VERSION 5.7 ;
BUSBITCHARS "[]" ;
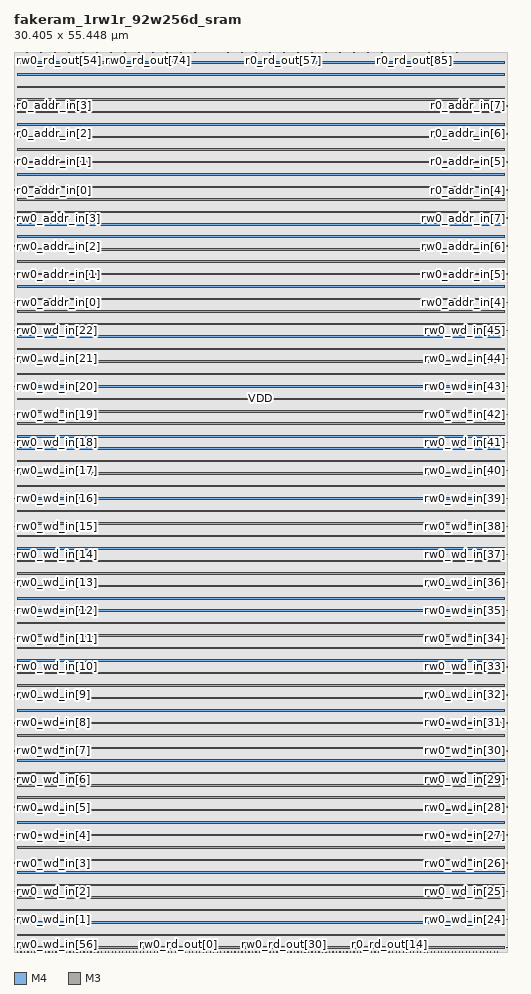
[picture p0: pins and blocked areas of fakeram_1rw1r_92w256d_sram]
MACRO fakeram_1rw1r_92w256d_sram
  FOREIGN fakeram_1rw1r_92w256d_sram 0 0 ;
  SYMMETRY X Y R90 ;
  SIZE 30.405 BY 55.448 ;
  CLASS BLOCK ;
  PIN rw0_wd_in[0]
    DIRECTION INPUT ;
    USE SIGNAL ;
    SHAPE ABUTMENT ;
    PORT
      LAYER M4 ;
      RECT 0.000 0.276 0.072 0.300 ;
    END
  END rw0_wd_in[0]
  PIN rw0_wd_in[1]
    DIRECTION INPUT ;
    USE SIGNAL ;
    SHAPE ABUTMENT ;
    PORT
      LAYER M4 ;
      RECT 0.000 2.004 0.072 2.028 ;
    END
  END rw0_wd_in[1]
  PIN rw0_wd_in[2]
    DIRECTION INPUT ;
    USE SIGNAL ;
    SHAPE ABUTMENT ;
    PORT
      LAYER M4 ;
      RECT 0.000 3.732 0.072 3.756 ;
    END
  END rw0_wd_in[2]
  PIN rw0_wd_in[3]
    DIRECTION INPUT ;
    USE SIGNAL ;
    SHAPE ABUTMENT ;
    PORT
      LAYER M4 ;
      RECT 0.000 5.460 0.072 5.484 ;
    END
  END rw0_wd_in[3]
  PIN rw0_wd_in[4]
    DIRECTION INPUT ;
    USE SIGNAL ;
    SHAPE ABUTMENT ;
    PORT
      LAYER M4 ;
      RECT 0.000 7.188 0.072 7.212 ;
    END
  END rw0_wd_in[4]
  PIN rw0_wd_in[5]
    DIRECTION INPUT ;
    USE SIGNAL ;
    SHAPE ABUTMENT ;
    PORT
      LAYER M4 ;
      RECT 0.000 8.916 0.072 8.940 ;
    END
  END rw0_wd_in[5]
  PIN rw0_wd_in[6]
    DIRECTION INPUT ;
    USE SIGNAL ;
    SHAPE ABUTMENT ;
    PORT
      LAYER M4 ;
      RECT 0.000 10.644 0.072 10.668 ;
    END
  END rw0_wd_in[6]
  PIN rw0_wd_in[7]
    DIRECTION INPUT ;
    USE SIGNAL ;
    SHAPE ABUTMENT ;
    PORT
      LAYER M4 ;
      RECT 0.000 12.372 0.072 12.396 ;
    END
  END rw0_wd_in[7]
  PIN rw0_wd_in[8]
    DIRECTION INPUT ;
    USE SIGNAL ;
    SHAPE ABUTMENT ;
    PORT
      LAYER M4 ;
      RECT 0.000 14.100 0.072 14.124 ;
    END
  END rw0_wd_in[8]
  PIN rw0_wd_in[9]
    DIRECTION INPUT ;
    USE SIGNAL ;
    SHAPE ABUTMENT ;
    PORT
      LAYER M4 ;
      RECT 0.000 15.828 0.072 15.852 ;
    END
  END rw0_wd_in[9]
  PIN rw0_wd_in[10]
    DIRECTION INPUT ;
    USE SIGNAL ;
    SHAPE ABUTMENT ;
    PORT
      LAYER M4 ;
      RECT 0.000 17.556 0.072 17.580 ;
    END
  END rw0_wd_in[10]
  PIN rw0_wd_in[11]
    DIRECTION INPUT ;
    USE SIGNAL ;
    SHAPE ABUTMENT ;
    PORT
      LAYER M4 ;
      RECT 0.000 19.284 0.072 19.308 ;
    END
  END rw0_wd_in[11]
  PIN rw0_wd_in[12]
    DIRECTION INPUT ;
    USE SIGNAL ;
    SHAPE ABUTMENT ;
    PORT
      LAYER M4 ;
      RECT 0.000 21.012 0.072 21.036 ;
    END
  END rw0_wd_in[12]
  PIN rw0_wd_in[13]
    DIRECTION INPUT ;
    USE SIGNAL ;
    SHAPE ABUTMENT ;
    PORT
      LAYER M4 ;
      RECT 0.000 22.740 0.072 22.764 ;
    END
  END rw0_wd_in[13]
  PIN rw0_wd_in[14]
    DIRECTION INPUT ;
    USE SIGNAL ;
    SHAPE ABUTMENT ;
    PORT
      LAYER M4 ;
      RECT 0.000 24.468 0.072 24.492 ;
    END
  END rw0_wd_in[14]
  PIN rw0_wd_in[15]
    DIRECTION INPUT ;
    USE SIGNAL ;
    SHAPE ABUTMENT ;
    PORT
      LAYER M4 ;
      RECT 0.000 26.196 0.072 26.220 ;
    END
  END rw0_wd_in[15]
  PIN rw0_wd_in[16]
    DIRECTION INPUT ;
    USE SIGNAL ;
    SHAPE ABUTMENT ;
    PORT
      LAYER M4 ;
      RECT 0.000 27.924 0.072 27.948 ;
    END
  END rw0_wd_in[16]
  PIN rw0_wd_in[17]
    DIRECTION INPUT ;
    USE SIGNAL ;
    SHAPE ABUTMENT ;
    PORT
      LAYER M4 ;
      RECT 0.000 29.652 0.072 29.676 ;
    END
  END rw0_wd_in[17]
  PIN rw0_wd_in[18]
    DIRECTION INPUT ;
    USE SIGNAL ;
    SHAPE ABUTMENT ;
    PORT
      LAYER M4 ;
      RECT 0.000 31.380 0.072 31.404 ;
    END
  END rw0_wd_in[18]
  PIN rw0_wd_in[19]
    DIRECTION INPUT ;
    USE SIGNAL ;
    SHAPE ABUTMENT ;
    PORT
      LAYER M4 ;
      RECT 0.000 33.108 0.072 33.132 ;
    END
  END rw0_wd_in[19]
  PIN rw0_wd_in[20]
    DIRECTION INPUT ;
    USE SIGNAL ;
    SHAPE ABUTMENT ;
    PORT
      LAYER M4 ;
      RECT 0.000 34.836 0.072 34.860 ;
    END
  END rw0_wd_in[20]
  PIN rw0_wd_in[21]
    DIRECTION INPUT ;
    USE SIGNAL ;
    SHAPE ABUTMENT ;
    PORT
      LAYER M4 ;
      RECT 0.000 36.564 0.072 36.588 ;
    END
  END rw0_wd_in[21]
  PIN rw0_wd_in[22]
    DIRECTION INPUT ;
    USE SIGNAL ;
    SHAPE ABUTMENT ;
    PORT
      LAYER M4 ;
      RECT 0.000 38.292 0.072 38.316 ;
    END
  END rw0_wd_in[22]
  PIN rw0_wd_in[23]
    DIRECTION INPUT ;
    USE SIGNAL ;
    SHAPE ABUTMENT ;
    PORT
      LAYER M4 ;
      RECT 30.333 0.276 30.405 0.300 ;
    END
  END rw0_wd_in[23]
  PIN rw0_wd_in[24]
    DIRECTION INPUT ;
    USE SIGNAL ;
    SHAPE ABUTMENT ;
    PORT
      LAYER M4 ;
      RECT 30.333 2.004 30.405 2.028 ;
    END
  END rw0_wd_in[24]
  PIN rw0_wd_in[25]
    DIRECTION INPUT ;
    USE SIGNAL ;
    SHAPE ABUTMENT ;
    PORT
      LAYER M4 ;
      RECT 30.333 3.732 30.405 3.756 ;
    END
  END rw0_wd_in[25]
  PIN rw0_wd_in[26]
    DIRECTION INPUT ;
    USE SIGNAL ;
    SHAPE ABUTMENT ;
    PORT
      LAYER M4 ;
      RECT 30.333 5.460 30.405 5.484 ;
    END
  END rw0_wd_in[26]
  PIN rw0_wd_in[27]
    DIRECTION INPUT ;
    USE SIGNAL ;
    SHAPE ABUTMENT ;
    PORT
      LAYER M4 ;
      RECT 30.333 7.188 30.405 7.212 ;
    END
  END rw0_wd_in[27]
  PIN rw0_wd_in[28]
    DIRECTION INPUT ;
    USE SIGNAL ;
    SHAPE ABUTMENT ;
    PORT
      LAYER M4 ;
      RECT 30.333 8.916 30.405 8.940 ;
    END
  END rw0_wd_in[28]
  PIN rw0_wd_in[29]
    DIRECTION INPUT ;
    USE SIGNAL ;
    SHAPE ABUTMENT ;
    PORT
      LAYER M4 ;
      RECT 30.333 10.644 30.405 10.668 ;
    END
  END rw0_wd_in[29]
  PIN rw0_wd_in[30]
    DIRECTION INPUT ;
    USE SIGNAL ;
    SHAPE ABUTMENT ;
    PORT
      LAYER M4 ;
      RECT 30.333 12.372 30.405 12.396 ;
    END
  END rw0_wd_in[30]
  PIN rw0_wd_in[31]
    DIRECTION INPUT ;
    USE SIGNAL ;
    SHAPE ABUTMENT ;
    PORT
      LAYER M4 ;
      RECT 30.333 14.100 30.405 14.124 ;
    END
  END rw0_wd_in[31]
  PIN rw0_wd_in[32]
    DIRECTION INPUT ;
    USE SIGNAL ;
    SHAPE ABUTMENT ;
    PORT
      LAYER M4 ;
      RECT 30.333 15.828 30.405 15.852 ;
    END
  END rw0_wd_in[32]
  PIN rw0_wd_in[33]
    DIRECTION INPUT ;
    USE SIGNAL ;
    SHAPE ABUTMENT ;
    PORT
      LAYER M4 ;
      RECT 30.333 17.556 30.405 17.580 ;
    END
  END rw0_wd_in[33]
  PIN rw0_wd_in[34]
    DIRECTION INPUT ;
    USE SIGNAL ;
    SHAPE ABUTMENT ;
    PORT
      LAYER M4 ;
      RECT 30.333 19.284 30.405 19.308 ;
    END
  END rw0_wd_in[34]
  PIN rw0_wd_in[35]
    DIRECTION INPUT ;
    USE SIGNAL ;
    SHAPE ABUTMENT ;
    PORT
      LAYER M4 ;
      RECT 30.333 21.012 30.405 21.036 ;
    END
  END rw0_wd_in[35]
  PIN rw0_wd_in[36]
    DIRECTION INPUT ;
    USE SIGNAL ;
    SHAPE ABUTMENT ;
    PORT
      LAYER M4 ;
      RECT 30.333 22.740 30.405 22.764 ;
    END
  END rw0_wd_in[36]
  PIN rw0_wd_in[37]
    DIRECTION INPUT ;
    USE SIGNAL ;
    SHAPE ABUTMENT ;
    PORT
      LAYER M4 ;
      RECT 30.333 24.468 30.405 24.492 ;
    END
  END rw0_wd_in[37]
  PIN rw0_wd_in[38]
    DIRECTION INPUT ;
    USE SIGNAL ;
    SHAPE ABUTMENT ;
    PORT
      LAYER M4 ;
      RECT 30.333 26.196 30.405 26.220 ;
    END
  END rw0_wd_in[38]
  PIN rw0_wd_in[39]
    DIRECTION INPUT ;
    USE SIGNAL ;
    SHAPE ABUTMENT ;
    PORT
      LAYER M4 ;
      RECT 30.333 27.924 30.405 27.948 ;
    END
  END rw0_wd_in[39]
  PIN rw0_wd_in[40]
    DIRECTION INPUT ;
    USE SIGNAL ;
    SHAPE ABUTMENT ;
    PORT
      LAYER M4 ;
      RECT 30.333 29.652 30.405 29.676 ;
    END
  END rw0_wd_in[40]
  PIN rw0_wd_in[41]
    DIRECTION INPUT ;
    USE SIGNAL ;
    SHAPE ABUTMENT ;
    PORT
      LAYER M4 ;
      RECT 30.333 31.380 30.405 31.404 ;
    END
  END rw0_wd_in[41]
  PIN rw0_wd_in[42]
    DIRECTION INPUT ;
    USE SIGNAL ;
    SHAPE ABUTMENT ;
    PORT
      LAYER M4 ;
      RECT 30.333 33.108 30.405 33.132 ;
    END
  END rw0_wd_in[42]
  PIN rw0_wd_in[43]
    DIRECTION INPUT ;
    USE SIGNAL ;
    SHAPE ABUTMENT ;
    PORT
      LAYER M4 ;
      RECT 30.333 34.836 30.405 34.860 ;
    END
  END rw0_wd_in[43]
  PIN rw0_wd_in[44]
    DIRECTION INPUT ;
    USE SIGNAL ;
    SHAPE ABUTMENT ;
    PORT
      LAYER M4 ;
      RECT 30.333 36.564 30.405 36.588 ;
    END
  END rw0_wd_in[44]
  PIN rw0_wd_in[45]
    DIRECTION INPUT ;
    USE SIGNAL ;
    SHAPE ABUTMENT ;
    PORT
      LAYER M4 ;
      RECT 30.333 38.292 30.405 38.316 ;
    END
  END rw0_wd_in[45]
  PIN rw0_wd_in[46]
    DIRECTION OUTPUT ;
    USE SIGNAL ;
    SHAPE ABUTMENT ;
    PORT
      LAYER M3 ;
      RECT 0.207 0.000 0.225 0.054 ;
    END
  END rw0_wd_in[46]
  PIN rw0_wd_in[47]
    DIRECTION OUTPUT ;
    USE SIGNAL ;
    SHAPE ABUTMENT ;
    PORT
      LAYER M3 ;
      RECT 0.423 0.000 0.441 0.054 ;
    END
  END rw0_wd_in[47]
  PIN rw0_wd_in[48]
    DIRECTION OUTPUT ;
    USE SIGNAL ;
    SHAPE ABUTMENT ;
    PORT
      LAYER M3 ;
      RECT 0.639 0.000 0.657 0.054 ;
    END
  END rw0_wd_in[48]
  PIN rw0_wd_in[49]
    DIRECTION OUTPUT ;
    USE SIGNAL ;
    SHAPE ABUTMENT ;
    PORT
      LAYER M3 ;
      RECT 0.855 0.000 0.873 0.054 ;
    END
  END rw0_wd_in[49]
  PIN rw0_wd_in[50]
    DIRECTION OUTPUT ;
    USE SIGNAL ;
    SHAPE ABUTMENT ;
    PORT
      LAYER M3 ;
      RECT 1.071 0.000 1.089 0.054 ;
    END
  END rw0_wd_in[50]
  PIN rw0_wd_in[51]
    DIRECTION OUTPUT ;
    USE SIGNAL ;
    SHAPE ABUTMENT ;
    PORT
      LAYER M3 ;
      RECT 1.287 0.000 1.305 0.054 ;
    END
  END rw0_wd_in[51]
  PIN rw0_wd_in[52]
    DIRECTION OUTPUT ;
    USE SIGNAL ;
    SHAPE ABUTMENT ;
    PORT
      LAYER M3 ;
      RECT 1.503 0.000 1.521 0.054 ;
    END
  END rw0_wd_in[52]
  PIN rw0_wd_in[53]
    DIRECTION OUTPUT ;
    USE SIGNAL ;
    SHAPE ABUTMENT ;
    PORT
      LAYER M3 ;
      RECT 1.719 0.000 1.737 0.054 ;
    END
  END rw0_wd_in[53]
  PIN rw0_wd_in[54]
    DIRECTION OUTPUT ;
    USE SIGNAL ;
    SHAPE ABUTMENT ;
    PORT
      LAYER M3 ;
      RECT 1.935 0.000 1.953 0.054 ;
    END
  END rw0_wd_in[54]
  PIN rw0_wd_in[55]
    DIRECTION OUTPUT ;
    USE SIGNAL ;
    SHAPE ABUTMENT ;
    PORT
      LAYER M3 ;
      RECT 2.151 0.000 2.169 0.054 ;
    END
  END rw0_wd_in[55]
  PIN rw0_wd_in[56]
    DIRECTION OUTPUT ;
    USE SIGNAL ;
    SHAPE ABUTMENT ;
    PORT
      LAYER M3 ;
      RECT 2.367 0.000 2.385 0.054 ;
    END
  END rw0_wd_in[56]
  PIN rw0_wd_in[57]
    DIRECTION OUTPUT ;
    USE SIGNAL ;
    SHAPE ABUTMENT ;
    PORT
      LAYER M3 ;
      RECT 2.583 0.000 2.601 0.054 ;
    END
  END rw0_wd_in[57]
  PIN rw0_wd_in[58]
    DIRECTION OUTPUT ;
    USE SIGNAL ;
    SHAPE ABUTMENT ;
    PORT
      LAYER M3 ;
      RECT 2.799 0.000 2.817 0.054 ;
    END
  END rw0_wd_in[58]
  PIN rw0_wd_in[59]
    DIRECTION OUTPUT ;
    USE SIGNAL ;
    SHAPE ABUTMENT ;
    PORT
      LAYER M3 ;
      RECT 3.015 0.000 3.033 0.054 ;
    END
  END rw0_wd_in[59]
  PIN rw0_wd_in[60]
    DIRECTION OUTPUT ;
    USE SIGNAL ;
    SHAPE ABUTMENT ;
    PORT
      LAYER M3 ;
      RECT 3.231 0.000 3.249 0.054 ;
    END
  END rw0_wd_in[60]
  PIN rw0_wd_in[61]
    DIRECTION OUTPUT ;
    USE SIGNAL ;
    SHAPE ABUTMENT ;
    PORT
      LAYER M3 ;
      RECT 3.447 0.000 3.465 0.054 ;
    END
  END rw0_wd_in[61]
  PIN rw0_wd_in[62]
    DIRECTION OUTPUT ;
    USE SIGNAL ;
    SHAPE ABUTMENT ;
    PORT
      LAYER M3 ;
      RECT 3.663 0.000 3.681 0.054 ;
    END
  END rw0_wd_in[62]
  PIN rw0_wd_in[63]
    DIRECTION OUTPUT ;
    USE SIGNAL ;
    SHAPE ABUTMENT ;
    PORT
      LAYER M3 ;
      RECT 3.879 0.000 3.897 0.054 ;
    END
  END rw0_wd_in[63]
  PIN rw0_wd_in[64]
    DIRECTION OUTPUT ;
    USE SIGNAL ;
    SHAPE ABUTMENT ;
    PORT
      LAYER M3 ;
      RECT 4.095 0.000 4.113 0.054 ;
    END
  END rw0_wd_in[64]
  PIN rw0_wd_in[65]
    DIRECTION OUTPUT ;
    USE SIGNAL ;
    SHAPE ABUTMENT ;
    PORT
      LAYER M3 ;
      RECT 4.311 0.000 4.329 0.054 ;
    END
  END rw0_wd_in[65]
  PIN rw0_wd_in[66]
    DIRECTION OUTPUT ;
    USE SIGNAL ;
    SHAPE ABUTMENT ;
    PORT
      LAYER M3 ;
      RECT 4.527 0.000 4.545 0.054 ;
    END
  END rw0_wd_in[66]
  PIN rw0_wd_in[67]
    DIRECTION OUTPUT ;
    USE SIGNAL ;
    SHAPE ABUTMENT ;
    PORT
      LAYER M3 ;
      RECT 4.743 0.000 4.761 0.054 ;
    END
  END rw0_wd_in[67]
  PIN rw0_wd_in[68]
    DIRECTION OUTPUT ;
    USE SIGNAL ;
    SHAPE ABUTMENT ;
    PORT
      LAYER M3 ;
      RECT 4.959 0.000 4.977 0.054 ;
    END
  END rw0_wd_in[68]
  PIN rw0_wd_in[69]
    DIRECTION OUTPUT ;
    USE SIGNAL ;
    SHAPE ABUTMENT ;
    PORT
      LAYER M3 ;
      RECT 5.175 0.000 5.193 0.054 ;
    END
  END rw0_wd_in[69]
  PIN rw0_wd_in[70]
    DIRECTION OUTPUT ;
    USE SIGNAL ;
    SHAPE ABUTMENT ;
    PORT
      LAYER M3 ;
      RECT 5.391 0.000 5.409 0.054 ;
    END
  END rw0_wd_in[70]
  PIN rw0_wd_in[71]
    DIRECTION OUTPUT ;
    USE SIGNAL ;
    SHAPE ABUTMENT ;
    PORT
      LAYER M3 ;
      RECT 5.607 0.000 5.625 0.054 ;
    END
  END rw0_wd_in[71]
  PIN rw0_wd_in[72]
    DIRECTION OUTPUT ;
    USE SIGNAL ;
    SHAPE ABUTMENT ;
    PORT
      LAYER M3 ;
      RECT 5.823 0.000 5.841 0.054 ;
    END
  END rw0_wd_in[72]
  PIN rw0_wd_in[73]
    DIRECTION OUTPUT ;
    USE SIGNAL ;
    SHAPE ABUTMENT ;
    PORT
      LAYER M3 ;
      RECT 6.039 0.000 6.057 0.054 ;
    END
  END rw0_wd_in[73]
  PIN rw0_wd_in[74]
    DIRECTION OUTPUT ;
    USE SIGNAL ;
    SHAPE ABUTMENT ;
    PORT
      LAYER M3 ;
      RECT 6.255 0.000 6.273 0.054 ;
    END
  END rw0_wd_in[74]
  PIN rw0_wd_in[75]
    DIRECTION OUTPUT ;
    USE SIGNAL ;
    SHAPE ABUTMENT ;
    PORT
      LAYER M3 ;
      RECT 6.471 0.000 6.489 0.054 ;
    END
  END rw0_wd_in[75]
  PIN rw0_wd_in[76]
    DIRECTION OUTPUT ;
    USE SIGNAL ;
    SHAPE ABUTMENT ;
    PORT
      LAYER M3 ;
      RECT 6.687 0.000 6.705 0.054 ;
    END
  END rw0_wd_in[76]
  PIN rw0_wd_in[77]
    DIRECTION OUTPUT ;
    USE SIGNAL ;
    SHAPE ABUTMENT ;
    PORT
      LAYER M3 ;
      RECT 6.903 0.000 6.921 0.054 ;
    END
  END rw0_wd_in[77]
  PIN rw0_wd_in[78]
    DIRECTION OUTPUT ;
    USE SIGNAL ;
    SHAPE ABUTMENT ;
    PORT
      LAYER M3 ;
      RECT 7.119 0.000 7.137 0.054 ;
    END
  END rw0_wd_in[78]
  PIN rw0_wd_in[79]
    DIRECTION OUTPUT ;
    USE SIGNAL ;
    SHAPE ABUTMENT ;
    PORT
      LAYER M3 ;
      RECT 7.335 0.000 7.353 0.054 ;
    END
  END rw0_wd_in[79]
  PIN rw0_wd_in[80]
    DIRECTION OUTPUT ;
    USE SIGNAL ;
    SHAPE ABUTMENT ;
    PORT
      LAYER M3 ;
      RECT 7.551 0.000 7.569 0.054 ;
    END
  END rw0_wd_in[80]
  PIN rw0_wd_in[81]
    DIRECTION OUTPUT ;
    USE SIGNAL ;
    SHAPE ABUTMENT ;
    PORT
      LAYER M3 ;
      RECT 7.767 0.000 7.785 0.054 ;
    END
  END rw0_wd_in[81]
  PIN rw0_wd_in[82]
    DIRECTION OUTPUT ;
    USE SIGNAL ;
    SHAPE ABUTMENT ;
    PORT
      LAYER M3 ;
      RECT 7.983 0.000 8.001 0.054 ;
    END
  END rw0_wd_in[82]
  PIN rw0_wd_in[83]
    DIRECTION OUTPUT ;
    USE SIGNAL ;
    SHAPE ABUTMENT ;
    PORT
      LAYER M3 ;
      RECT 8.199 0.000 8.217 0.054 ;
    END
  END rw0_wd_in[83]
  PIN rw0_wd_in[84]
    DIRECTION OUTPUT ;
    USE SIGNAL ;
    SHAPE ABUTMENT ;
    PORT
      LAYER M3 ;
      RECT 8.415 0.000 8.433 0.054 ;
    END
  END rw0_wd_in[84]
  PIN rw0_wd_in[85]
    DIRECTION OUTPUT ;
    USE SIGNAL ;
    SHAPE ABUTMENT ;
    PORT
      LAYER M3 ;
      RECT 8.631 0.000 8.649 0.054 ;
    END
  END rw0_wd_in[85]
  PIN rw0_wd_in[86]
    DIRECTION OUTPUT ;
    USE SIGNAL ;
    SHAPE ABUTMENT ;
    PORT
      LAYER M3 ;
      RECT 8.847 0.000 8.865 0.054 ;
    END
  END rw0_wd_in[86]
  PIN rw0_wd_in[87]
    DIRECTION OUTPUT ;
    USE SIGNAL ;
    SHAPE ABUTMENT ;
    PORT
      LAYER M3 ;
      RECT 9.063 0.000 9.081 0.054 ;
    END
  END rw0_wd_in[87]
  PIN rw0_wd_in[88]
    DIRECTION OUTPUT ;
    USE SIGNAL ;
    SHAPE ABUTMENT ;
    PORT
      LAYER M3 ;
      RECT 9.279 0.000 9.297 0.054 ;
    END
  END rw0_wd_in[88]
  PIN rw0_wd_in[89]
    DIRECTION OUTPUT ;
    USE SIGNAL ;
    SHAPE ABUTMENT ;
    PORT
      LAYER M3 ;
      RECT 9.495 0.000 9.513 0.054 ;
    END
  END rw0_wd_in[89]
  PIN rw0_wd_in[90]
    DIRECTION OUTPUT ;
    USE SIGNAL ;
    SHAPE ABUTMENT ;
    PORT
      LAYER M3 ;
      RECT 9.711 0.000 9.729 0.054 ;
    END
  END rw0_wd_in[90]
  PIN rw0_wd_in[91]
    DIRECTION OUTPUT ;
    USE SIGNAL ;
    SHAPE ABUTMENT ;
    PORT
      LAYER M3 ;
      RECT 9.927 0.000 9.945 0.054 ;
    END
  END rw0_wd_in[91]
  PIN rw0_rd_out[0]
    DIRECTION OUTPUT ;
    USE SIGNAL ;
    SHAPE ABUTMENT ;
    PORT
      LAYER M3 ;
      RECT 10.143 0.000 10.161 0.054 ;
    END
  END rw0_rd_out[0]
  PIN rw0_rd_out[1]
    DIRECTION OUTPUT ;
    USE SIGNAL ;
    SHAPE ABUTMENT ;
    PORT
      LAYER M3 ;
      RECT 10.359 0.000 10.377 0.054 ;
    END
  END rw0_rd_out[1]
  PIN rw0_rd_out[2]
    DIRECTION OUTPUT ;
    USE SIGNAL ;
    SHAPE ABUTMENT ;
    PORT
      LAYER M3 ;
      RECT 10.575 0.000 10.593 0.054 ;
    END
  END rw0_rd_out[2]
  PIN rw0_rd_out[3]
    DIRECTION OUTPUT ;
    USE SIGNAL ;
    SHAPE ABUTMENT ;
    PORT
      LAYER M3 ;
      RECT 10.791 0.000 10.809 0.054 ;
    END
  END rw0_rd_out[3]
  PIN rw0_rd_out[4]
    DIRECTION OUTPUT ;
    USE SIGNAL ;
    SHAPE ABUTMENT ;
    PORT
      LAYER M3 ;
      RECT 11.007 0.000 11.025 0.054 ;
    END
  END rw0_rd_out[4]
  PIN rw0_rd_out[5]
    DIRECTION OUTPUT ;
    USE SIGNAL ;
    SHAPE ABUTMENT ;
    PORT
      LAYER M3 ;
      RECT 11.223 0.000 11.241 0.054 ;
    END
  END rw0_rd_out[5]
  PIN rw0_rd_out[6]
    DIRECTION OUTPUT ;
    USE SIGNAL ;
    SHAPE ABUTMENT ;
    PORT
      LAYER M3 ;
      RECT 11.439 0.000 11.457 0.054 ;
    END
  END rw0_rd_out[6]
  PIN rw0_rd_out[7]
    DIRECTION OUTPUT ;
    USE SIGNAL ;
    SHAPE ABUTMENT ;
    PORT
      LAYER M3 ;
      RECT 11.655 0.000 11.673 0.054 ;
    END
  END rw0_rd_out[7]
  PIN rw0_rd_out[8]
    DIRECTION OUTPUT ;
    USE SIGNAL ;
    SHAPE ABUTMENT ;
    PORT
      LAYER M3 ;
      RECT 11.871 0.000 11.889 0.054 ;
    END
  END rw0_rd_out[8]
  PIN rw0_rd_out[9]
    DIRECTION OUTPUT ;
    USE SIGNAL ;
    SHAPE ABUTMENT ;
    PORT
      LAYER M3 ;
      RECT 12.087 0.000 12.105 0.054 ;
    END
  END rw0_rd_out[9]
  PIN rw0_rd_out[10]
    DIRECTION OUTPUT ;
    USE SIGNAL ;
    SHAPE ABUTMENT ;
    PORT
      LAYER M3 ;
      RECT 12.303 0.000 12.321 0.054 ;
    END
  END rw0_rd_out[10]
  PIN rw0_rd_out[11]
    DIRECTION OUTPUT ;
    USE SIGNAL ;
    SHAPE ABUTMENT ;
    PORT
      LAYER M3 ;
      RECT 12.519 0.000 12.537 0.054 ;
    END
  END rw0_rd_out[11]
  PIN rw0_rd_out[12]
    DIRECTION OUTPUT ;
    USE SIGNAL ;
    SHAPE ABUTMENT ;
    PORT
      LAYER M3 ;
      RECT 12.735 0.000 12.753 0.054 ;
    END
  END rw0_rd_out[12]
  PIN rw0_rd_out[13]
    DIRECTION OUTPUT ;
    USE SIGNAL ;
    SHAPE ABUTMENT ;
    PORT
      LAYER M3 ;
      RECT 12.951 0.000 12.969 0.054 ;
    END
  END rw0_rd_out[13]
  PIN rw0_rd_out[14]
    DIRECTION OUTPUT ;
    USE SIGNAL ;
    SHAPE ABUTMENT ;
    PORT
      LAYER M3 ;
      RECT 13.167 0.000 13.185 0.054 ;
    END
  END rw0_rd_out[14]
  PIN rw0_rd_out[15]
    DIRECTION OUTPUT ;
    USE SIGNAL ;
    SHAPE ABUTMENT ;
    PORT
      LAYER M3 ;
      RECT 13.383 0.000 13.401 0.054 ;
    END
  END rw0_rd_out[15]
  PIN rw0_rd_out[16]
    DIRECTION OUTPUT ;
    USE SIGNAL ;
    SHAPE ABUTMENT ;
    PORT
      LAYER M3 ;
      RECT 13.599 0.000 13.617 0.054 ;
    END
  END rw0_rd_out[16]
  PIN rw0_rd_out[17]
    DIRECTION OUTPUT ;
    USE SIGNAL ;
    SHAPE ABUTMENT ;
    PORT
      LAYER M3 ;
      RECT 13.815 0.000 13.833 0.054 ;
    END
  END rw0_rd_out[17]
  PIN rw0_rd_out[18]
    DIRECTION OUTPUT ;
    USE SIGNAL ;
    SHAPE ABUTMENT ;
    PORT
      LAYER M3 ;
      RECT 14.031 0.000 14.049 0.054 ;
    END
  END rw0_rd_out[18]
  PIN rw0_rd_out[19]
    DIRECTION OUTPUT ;
    USE SIGNAL ;
    SHAPE ABUTMENT ;
    PORT
      LAYER M3 ;
      RECT 14.247 0.000 14.265 0.054 ;
    END
  END rw0_rd_out[19]
  PIN rw0_rd_out[20]
    DIRECTION OUTPUT ;
    USE SIGNAL ;
    SHAPE ABUTMENT ;
    PORT
      LAYER M3 ;
      RECT 14.463 0.000 14.481 0.054 ;
    END
  END rw0_rd_out[20]
  PIN rw0_rd_out[21]
    DIRECTION OUTPUT ;
    USE SIGNAL ;
    SHAPE ABUTMENT ;
    PORT
      LAYER M3 ;
      RECT 14.679 0.000 14.697 0.054 ;
    END
  END rw0_rd_out[21]
  PIN rw0_rd_out[22]
    DIRECTION OUTPUT ;
    USE SIGNAL ;
    SHAPE ABUTMENT ;
    PORT
      LAYER M3 ;
      RECT 14.895 0.000 14.913 0.054 ;
    END
  END rw0_rd_out[22]
  PIN rw0_rd_out[23]
    DIRECTION OUTPUT ;
    USE SIGNAL ;
    SHAPE ABUTMENT ;
    PORT
      LAYER M3 ;
      RECT 15.111 0.000 15.129 0.054 ;
    END
  END rw0_rd_out[23]
  PIN rw0_rd_out[24]
    DIRECTION OUTPUT ;
    USE SIGNAL ;
    SHAPE ABUTMENT ;
    PORT
      LAYER M3 ;
      RECT 15.327 0.000 15.345 0.054 ;
    END
  END rw0_rd_out[24]
  PIN rw0_rd_out[25]
    DIRECTION OUTPUT ;
    USE SIGNAL ;
    SHAPE ABUTMENT ;
    PORT
      LAYER M3 ;
      RECT 15.543 0.000 15.561 0.054 ;
    END
  END rw0_rd_out[25]
  PIN rw0_rd_out[26]
    DIRECTION OUTPUT ;
    USE SIGNAL ;
    SHAPE ABUTMENT ;
    PORT
      LAYER M3 ;
      RECT 15.759 0.000 15.777 0.054 ;
    END
  END rw0_rd_out[26]
  PIN rw0_rd_out[27]
    DIRECTION OUTPUT ;
    USE SIGNAL ;
    SHAPE ABUTMENT ;
    PORT
      LAYER M3 ;
      RECT 15.975 0.000 15.993 0.054 ;
    END
  END rw0_rd_out[27]
  PIN rw0_rd_out[28]
    DIRECTION OUTPUT ;
    USE SIGNAL ;
    SHAPE ABUTMENT ;
    PORT
      LAYER M3 ;
      RECT 16.191 0.000 16.209 0.054 ;
    END
  END rw0_rd_out[28]
  PIN rw0_rd_out[29]
    DIRECTION OUTPUT ;
    USE SIGNAL ;
    SHAPE ABUTMENT ;
    PORT
      LAYER M3 ;
      RECT 16.407 0.000 16.425 0.054 ;
    END
  END rw0_rd_out[29]
  PIN rw0_rd_out[30]
    DIRECTION OUTPUT ;
    USE SIGNAL ;
    SHAPE ABUTMENT ;
    PORT
      LAYER M3 ;
      RECT 16.623 0.000 16.641 0.054 ;
    END
  END rw0_rd_out[30]
  PIN rw0_rd_out[31]
    DIRECTION OUTPUT ;
    USE SIGNAL ;
    SHAPE ABUTMENT ;
    PORT
      LAYER M3 ;
      RECT 16.839 0.000 16.857 0.054 ;
    END
  END rw0_rd_out[31]
  PIN rw0_rd_out[32]
    DIRECTION OUTPUT ;
    USE SIGNAL ;
    SHAPE ABUTMENT ;
    PORT
      LAYER M3 ;
      RECT 17.055 0.000 17.073 0.054 ;
    END
  END rw0_rd_out[32]
  PIN rw0_rd_out[33]
    DIRECTION OUTPUT ;
    USE SIGNAL ;
    SHAPE ABUTMENT ;
    PORT
      LAYER M3 ;
      RECT 17.271 0.000 17.289 0.054 ;
    END
  END rw0_rd_out[33]
  PIN rw0_rd_out[34]
    DIRECTION OUTPUT ;
    USE SIGNAL ;
    SHAPE ABUTMENT ;
    PORT
      LAYER M3 ;
      RECT 17.487 0.000 17.505 0.054 ;
    END
  END rw0_rd_out[34]
  PIN rw0_rd_out[35]
    DIRECTION OUTPUT ;
    USE SIGNAL ;
    SHAPE ABUTMENT ;
    PORT
      LAYER M3 ;
      RECT 17.703 0.000 17.721 0.054 ;
    END
  END rw0_rd_out[35]
  PIN rw0_rd_out[36]
    DIRECTION OUTPUT ;
    USE SIGNAL ;
    SHAPE ABUTMENT ;
    PORT
      LAYER M3 ;
      RECT 17.919 0.000 17.937 0.054 ;
    END
  END rw0_rd_out[36]
  PIN rw0_rd_out[37]
    DIRECTION OUTPUT ;
    USE SIGNAL ;
    SHAPE ABUTMENT ;
    PORT
      LAYER M3 ;
      RECT 18.135 0.000 18.153 0.054 ;
    END
  END rw0_rd_out[37]
  PIN rw0_rd_out[38]
    DIRECTION OUTPUT ;
    USE SIGNAL ;
    SHAPE ABUTMENT ;
    PORT
      LAYER M3 ;
      RECT 18.351 0.000 18.369 0.054 ;
    END
  END rw0_rd_out[38]
  PIN rw0_rd_out[39]
    DIRECTION OUTPUT ;
    USE SIGNAL ;
    SHAPE ABUTMENT ;
    PORT
      LAYER M3 ;
      RECT 18.567 0.000 18.585 0.054 ;
    END
  END rw0_rd_out[39]
  PIN rw0_rd_out[40]
    DIRECTION OUTPUT ;
    USE SIGNAL ;
    SHAPE ABUTMENT ;
    PORT
      LAYER M3 ;
      RECT 18.783 0.000 18.801 0.054 ;
    END
  END rw0_rd_out[40]
  PIN rw0_rd_out[41]
    DIRECTION OUTPUT ;
    USE SIGNAL ;
    SHAPE ABUTMENT ;
    PORT
      LAYER M3 ;
      RECT 18.999 0.000 19.017 0.054 ;
    END
  END rw0_rd_out[41]
  PIN rw0_rd_out[42]
    DIRECTION OUTPUT ;
    USE SIGNAL ;
    SHAPE ABUTMENT ;
    PORT
      LAYER M3 ;
      RECT 19.215 0.000 19.233 0.054 ;
    END
  END rw0_rd_out[42]
  PIN rw0_rd_out[43]
    DIRECTION OUTPUT ;
    USE SIGNAL ;
    SHAPE ABUTMENT ;
    PORT
      LAYER M3 ;
      RECT 19.431 0.000 19.449 0.054 ;
    END
  END rw0_rd_out[43]
  PIN rw0_rd_out[44]
    DIRECTION OUTPUT ;
    USE SIGNAL ;
    SHAPE ABUTMENT ;
    PORT
      LAYER M3 ;
      RECT 19.647 0.000 19.665 0.054 ;
    END
  END rw0_rd_out[44]
  PIN rw0_rd_out[45]
    DIRECTION OUTPUT ;
    USE SIGNAL ;
    SHAPE ABUTMENT ;
    PORT
      LAYER M3 ;
      RECT 19.863 0.000 19.881 0.054 ;
    END
  END rw0_rd_out[45]
  PIN rw0_rd_out[46]
    DIRECTION OUTPUT ;
    USE SIGNAL ;
    SHAPE ABUTMENT ;
    PORT
      LAYER M3 ;
      RECT 0.207 55.394 0.225 55.448 ;
    END
  END rw0_rd_out[46]
  PIN rw0_rd_out[47]
    DIRECTION OUTPUT ;
    USE SIGNAL ;
    SHAPE ABUTMENT ;
    PORT
      LAYER M3 ;
      RECT 0.495 55.394 0.513 55.448 ;
    END
  END rw0_rd_out[47]
  PIN rw0_rd_out[48]
    DIRECTION OUTPUT ;
    USE SIGNAL ;
    SHAPE ABUTMENT ;
    PORT
      LAYER M3 ;
      RECT 0.783 55.394 0.801 55.448 ;
    END
  END rw0_rd_out[48]
  PIN rw0_rd_out[49]
    DIRECTION OUTPUT ;
    USE SIGNAL ;
    SHAPE ABUTMENT ;
    PORT
      LAYER M3 ;
      RECT 1.071 55.394 1.089 55.448 ;
    END
  END rw0_rd_out[49]
  PIN rw0_rd_out[50]
    DIRECTION OUTPUT ;
    USE SIGNAL ;
    SHAPE ABUTMENT ;
    PORT
      LAYER M3 ;
      RECT 1.359 55.394 1.377 55.448 ;
    END
  END rw0_rd_out[50]
  PIN rw0_rd_out[51]
    DIRECTION OUTPUT ;
    USE SIGNAL ;
    SHAPE ABUTMENT ;
    PORT
      LAYER M3 ;
      RECT 1.647 55.394 1.665 55.448 ;
    END
  END rw0_rd_out[51]
  PIN rw0_rd_out[52]
    DIRECTION OUTPUT ;
    USE SIGNAL ;
    SHAPE ABUTMENT ;
    PORT
      LAYER M3 ;
      RECT 1.935 55.394 1.953 55.448 ;
    END
  END rw0_rd_out[52]
  PIN rw0_rd_out[53]
    DIRECTION OUTPUT ;
    USE SIGNAL ;
    SHAPE ABUTMENT ;
    PORT
      LAYER M3 ;
      RECT 2.223 55.394 2.241 55.448 ;
    END
  END rw0_rd_out[53]
  PIN rw0_rd_out[54]
    DIRECTION OUTPUT ;
    USE SIGNAL ;
    SHAPE ABUTMENT ;
    PORT
      LAYER M3 ;
      RECT 2.511 55.394 2.529 55.448 ;
    END
  END rw0_rd_out[54]
  PIN rw0_rd_out[55]
    DIRECTION OUTPUT ;
    USE SIGNAL ;
    SHAPE ABUTMENT ;
    PORT
      LAYER M3 ;
      RECT 2.799 55.394 2.817 55.448 ;
    END
  END rw0_rd_out[55]
  PIN rw0_rd_out[56]
    DIRECTION OUTPUT ;
    USE SIGNAL ;
    SHAPE ABUTMENT ;
    PORT
      LAYER M3 ;
      RECT 3.087 55.394 3.105 55.448 ;
    END
  END rw0_rd_out[56]
  PIN rw0_rd_out[57]
    DIRECTION OUTPUT ;
    USE SIGNAL ;
    SHAPE ABUTMENT ;
    PORT
      LAYER M3 ;
      RECT 3.375 55.394 3.393 55.448 ;
    END
  END rw0_rd_out[57]
  PIN rw0_rd_out[58]
    DIRECTION OUTPUT ;
    USE SIGNAL ;
    SHAPE ABUTMENT ;
    PORT
      LAYER M3 ;
      RECT 3.663 55.394 3.681 55.448 ;
    END
  END rw0_rd_out[58]
  PIN rw0_rd_out[59]
    DIRECTION OUTPUT ;
    USE SIGNAL ;
    SHAPE ABUTMENT ;
    PORT
      LAYER M3 ;
      RECT 3.951 55.394 3.969 55.448 ;
    END
  END rw0_rd_out[59]
  PIN rw0_rd_out[60]
    DIRECTION OUTPUT ;
    USE SIGNAL ;
    SHAPE ABUTMENT ;
    PORT
      LAYER M3 ;
      RECT 4.239 55.394 4.257 55.448 ;
    END
  END rw0_rd_out[60]
  PIN rw0_rd_out[61]
    DIRECTION OUTPUT ;
    USE SIGNAL ;
    SHAPE ABUTMENT ;
    PORT
      LAYER M3 ;
      RECT 4.527 55.394 4.545 55.448 ;
    END
  END rw0_rd_out[61]
  PIN rw0_rd_out[62]
    DIRECTION OUTPUT ;
    USE SIGNAL ;
    SHAPE ABUTMENT ;
    PORT
      LAYER M3 ;
      RECT 4.815 55.394 4.833 55.448 ;
    END
  END rw0_rd_out[62]
  PIN rw0_rd_out[63]
    DIRECTION OUTPUT ;
    USE SIGNAL ;
    SHAPE ABUTMENT ;
    PORT
      LAYER M3 ;
      RECT 5.103 55.394 5.121 55.448 ;
    END
  END rw0_rd_out[63]
  PIN rw0_rd_out[64]
    DIRECTION OUTPUT ;
    USE SIGNAL ;
    SHAPE ABUTMENT ;
    PORT
      LAYER M3 ;
      RECT 5.391 55.394 5.409 55.448 ;
    END
  END rw0_rd_out[64]
  PIN rw0_rd_out[65]
    DIRECTION OUTPUT ;
    USE SIGNAL ;
    SHAPE ABUTMENT ;
    PORT
      LAYER M3 ;
      RECT 5.679 55.394 5.697 55.448 ;
    END
  END rw0_rd_out[65]
  PIN rw0_rd_out[66]
    DIRECTION OUTPUT ;
    USE SIGNAL ;
    SHAPE ABUTMENT ;
    PORT
      LAYER M3 ;
      RECT 5.967 55.394 5.985 55.448 ;
    END
  END rw0_rd_out[66]
  PIN rw0_rd_out[67]
    DIRECTION OUTPUT ;
    USE SIGNAL ;
    SHAPE ABUTMENT ;
    PORT
      LAYER M3 ;
      RECT 6.255 55.394 6.273 55.448 ;
    END
  END rw0_rd_out[67]
  PIN rw0_rd_out[68]
    DIRECTION OUTPUT ;
    USE SIGNAL ;
    SHAPE ABUTMENT ;
    PORT
      LAYER M3 ;
      RECT 6.543 55.394 6.561 55.448 ;
    END
  END rw0_rd_out[68]
  PIN rw0_rd_out[69]
    DIRECTION OUTPUT ;
    USE SIGNAL ;
    SHAPE ABUTMENT ;
    PORT
      LAYER M3 ;
      RECT 6.831 55.394 6.849 55.448 ;
    END
  END rw0_rd_out[69]
  PIN rw0_rd_out[70]
    DIRECTION OUTPUT ;
    USE SIGNAL ;
    SHAPE ABUTMENT ;
    PORT
      LAYER M3 ;
      RECT 7.119 55.394 7.137 55.448 ;
    END
  END rw0_rd_out[70]
  PIN rw0_rd_out[71]
    DIRECTION OUTPUT ;
    USE SIGNAL ;
    SHAPE ABUTMENT ;
    PORT
      LAYER M3 ;
      RECT 7.407 55.394 7.425 55.448 ;
    END
  END rw0_rd_out[71]
  PIN rw0_rd_out[72]
    DIRECTION OUTPUT ;
    USE SIGNAL ;
    SHAPE ABUTMENT ;
    PORT
      LAYER M3 ;
      RECT 7.695 55.394 7.713 55.448 ;
    END
  END rw0_rd_out[72]
  PIN rw0_rd_out[73]
    DIRECTION OUTPUT ;
    USE SIGNAL ;
    SHAPE ABUTMENT ;
    PORT
      LAYER M3 ;
      RECT 7.983 55.394 8.001 55.448 ;
    END
  END rw0_rd_out[73]
  PIN rw0_rd_out[74]
    DIRECTION OUTPUT ;
    USE SIGNAL ;
    SHAPE ABUTMENT ;
    PORT
      LAYER M3 ;
      RECT 8.271 55.394 8.289 55.448 ;
    END
  END rw0_rd_out[74]
  PIN rw0_rd_out[75]
    DIRECTION OUTPUT ;
    USE SIGNAL ;
    SHAPE ABUTMENT ;
    PORT
      LAYER M3 ;
      RECT 8.559 55.394 8.577 55.448 ;
    END
  END rw0_rd_out[75]
  PIN rw0_rd_out[76]
    DIRECTION OUTPUT ;
    USE SIGNAL ;
    SHAPE ABUTMENT ;
    PORT
      LAYER M3 ;
      RECT 8.847 55.394 8.865 55.448 ;
    END
  END rw0_rd_out[76]
  PIN rw0_rd_out[77]
    DIRECTION OUTPUT ;
    USE SIGNAL ;
    SHAPE ABUTMENT ;
    PORT
      LAYER M3 ;
      RECT 9.135 55.394 9.153 55.448 ;
    END
  END rw0_rd_out[77]
  PIN rw0_rd_out[78]
    DIRECTION OUTPUT ;
    USE SIGNAL ;
    SHAPE ABUTMENT ;
    PORT
      LAYER M3 ;
      RECT 9.423 55.394 9.441 55.448 ;
    END
  END rw0_rd_out[78]
  PIN rw0_rd_out[79]
    DIRECTION OUTPUT ;
    USE SIGNAL ;
    SHAPE ABUTMENT ;
    PORT
      LAYER M3 ;
      RECT 9.711 55.394 9.729 55.448 ;
    END
  END rw0_rd_out[79]
  PIN rw0_rd_out[80]
    DIRECTION OUTPUT ;
    USE SIGNAL ;
    SHAPE ABUTMENT ;
    PORT
      LAYER M3 ;
      RECT 9.999 55.394 10.017 55.448 ;
    END
  END rw0_rd_out[80]
  PIN rw0_rd_out[81]
    DIRECTION OUTPUT ;
    USE SIGNAL ;
    SHAPE ABUTMENT ;
    PORT
      LAYER M3 ;
      RECT 10.287 55.394 10.305 55.448 ;
    END
  END rw0_rd_out[81]
  PIN rw0_rd_out[82]
    DIRECTION OUTPUT ;
    USE SIGNAL ;
    SHAPE ABUTMENT ;
    PORT
      LAYER M3 ;
      RECT 10.575 55.394 10.593 55.448 ;
    END
  END rw0_rd_out[82]
  PIN rw0_rd_out[83]
    DIRECTION OUTPUT ;
    USE SIGNAL ;
    SHAPE ABUTMENT ;
    PORT
      LAYER M3 ;
      RECT 10.863 55.394 10.881 55.448 ;
    END
  END rw0_rd_out[83]
  PIN rw0_rd_out[84]
    DIRECTION OUTPUT ;
    USE SIGNAL ;
    SHAPE ABUTMENT ;
    PORT
      LAYER M3 ;
      RECT 11.151 55.394 11.169 55.448 ;
    END
  END rw0_rd_out[84]
  PIN rw0_rd_out[85]
    DIRECTION OUTPUT ;
    USE SIGNAL ;
    SHAPE ABUTMENT ;
    PORT
      LAYER M3 ;
      RECT 11.439 55.394 11.457 55.448 ;
    END
  END rw0_rd_out[85]
  PIN rw0_rd_out[86]
    DIRECTION OUTPUT ;
    USE SIGNAL ;
    SHAPE ABUTMENT ;
    PORT
      LAYER M3 ;
      RECT 11.727 55.394 11.745 55.448 ;
    END
  END rw0_rd_out[86]
  PIN rw0_rd_out[87]
    DIRECTION OUTPUT ;
    USE SIGNAL ;
    SHAPE ABUTMENT ;
    PORT
      LAYER M3 ;
      RECT 12.015 55.394 12.033 55.448 ;
    END
  END rw0_rd_out[87]
  PIN rw0_rd_out[88]
    DIRECTION OUTPUT ;
    USE SIGNAL ;
    SHAPE ABUTMENT ;
    PORT
      LAYER M3 ;
      RECT 12.303 55.394 12.321 55.448 ;
    END
  END rw0_rd_out[88]
  PIN rw0_rd_out[89]
    DIRECTION OUTPUT ;
    USE SIGNAL ;
    SHAPE ABUTMENT ;
    PORT
      LAYER M3 ;
      RECT 12.591 55.394 12.609 55.448 ;
    END
  END rw0_rd_out[89]
  PIN rw0_rd_out[90]
    DIRECTION OUTPUT ;
    USE SIGNAL ;
    SHAPE ABUTMENT ;
    PORT
      LAYER M3 ;
      RECT 12.879 55.394 12.897 55.448 ;
    END
  END rw0_rd_out[90]
  PIN rw0_rd_out[91]
    DIRECTION OUTPUT ;
    USE SIGNAL ;
    SHAPE ABUTMENT ;
    PORT
      LAYER M3 ;
      RECT 13.167 55.394 13.185 55.448 ;
    END
  END rw0_rd_out[91]
  PIN r0_rd_out[0]
    DIRECTION OUTPUT ;
    USE SIGNAL ;
    SHAPE ABUTMENT ;
    PORT
      LAYER M3 ;
      RECT 20.079 0.000 20.097 0.054 ;
    END
  END r0_rd_out[0]
  PIN r0_rd_out[1]
    DIRECTION OUTPUT ;
    USE SIGNAL ;
    SHAPE ABUTMENT ;
    PORT
      LAYER M3 ;
      RECT 20.295 0.000 20.313 0.054 ;
    END
  END r0_rd_out[1]
  PIN r0_rd_out[2]
    DIRECTION OUTPUT ;
    USE SIGNAL ;
    SHAPE ABUTMENT ;
    PORT
      LAYER M3 ;
      RECT 20.511 0.000 20.529 0.054 ;
    END
  END r0_rd_out[2]
  PIN r0_rd_out[3]
    DIRECTION OUTPUT ;
    USE SIGNAL ;
    SHAPE ABUTMENT ;
    PORT
      LAYER M3 ;
      RECT 20.727 0.000 20.745 0.054 ;
    END
  END r0_rd_out[3]
  PIN r0_rd_out[4]
    DIRECTION OUTPUT ;
    USE SIGNAL ;
    SHAPE ABUTMENT ;
    PORT
      LAYER M3 ;
      RECT 20.943 0.000 20.961 0.054 ;
    END
  END r0_rd_out[4]
  PIN r0_rd_out[5]
    DIRECTION OUTPUT ;
    USE SIGNAL ;
    SHAPE ABUTMENT ;
    PORT
      LAYER M3 ;
      RECT 21.159 0.000 21.177 0.054 ;
    END
  END r0_rd_out[5]
  PIN r0_rd_out[6]
    DIRECTION OUTPUT ;
    USE SIGNAL ;
    SHAPE ABUTMENT ;
    PORT
      LAYER M3 ;
      RECT 21.375 0.000 21.393 0.054 ;
    END
  END r0_rd_out[6]
  PIN r0_rd_out[7]
    DIRECTION OUTPUT ;
    USE SIGNAL ;
    SHAPE ABUTMENT ;
    PORT
      LAYER M3 ;
      RECT 21.591 0.000 21.609 0.054 ;
    END
  END r0_rd_out[7]
  PIN r0_rd_out[8]
    DIRECTION OUTPUT ;
    USE SIGNAL ;
    SHAPE ABUTMENT ;
    PORT
      LAYER M3 ;
      RECT 21.807 0.000 21.825 0.054 ;
    END
  END r0_rd_out[8]
  PIN r0_rd_out[9]
    DIRECTION OUTPUT ;
    USE SIGNAL ;
    SHAPE ABUTMENT ;
    PORT
      LAYER M3 ;
      RECT 22.023 0.000 22.041 0.054 ;
    END
  END r0_rd_out[9]
  PIN r0_rd_out[10]
    DIRECTION OUTPUT ;
    USE SIGNAL ;
    SHAPE ABUTMENT ;
    PORT
      LAYER M3 ;
      RECT 22.239 0.000 22.257 0.054 ;
    END
  END r0_rd_out[10]
  PIN r0_rd_out[11]
    DIRECTION OUTPUT ;
    USE SIGNAL ;
    SHAPE ABUTMENT ;
    PORT
      LAYER M3 ;
      RECT 22.455 0.000 22.473 0.054 ;
    END
  END r0_rd_out[11]
  PIN r0_rd_out[12]
    DIRECTION OUTPUT ;
    USE SIGNAL ;
    SHAPE ABUTMENT ;
    PORT
      LAYER M3 ;
      RECT 22.671 0.000 22.689 0.054 ;
    END
  END r0_rd_out[12]
  PIN r0_rd_out[13]
    DIRECTION OUTPUT ;
    USE SIGNAL ;
    SHAPE ABUTMENT ;
    PORT
      LAYER M3 ;
      RECT 22.887 0.000 22.905 0.054 ;
    END
  END r0_rd_out[13]
  PIN r0_rd_out[14]
    DIRECTION OUTPUT ;
    USE SIGNAL ;
    SHAPE ABUTMENT ;
    PORT
      LAYER M3 ;
      RECT 23.103 0.000 23.121 0.054 ;
    END
  END r0_rd_out[14]
  PIN r0_rd_out[15]
    DIRECTION OUTPUT ;
    USE SIGNAL ;
    SHAPE ABUTMENT ;
    PORT
      LAYER M3 ;
      RECT 23.319 0.000 23.337 0.054 ;
    END
  END r0_rd_out[15]
  PIN r0_rd_out[16]
    DIRECTION OUTPUT ;
    USE SIGNAL ;
    SHAPE ABUTMENT ;
    PORT
      LAYER M3 ;
      RECT 23.535 0.000 23.553 0.054 ;
    END
  END r0_rd_out[16]
  PIN r0_rd_out[17]
    DIRECTION OUTPUT ;
    USE SIGNAL ;
    SHAPE ABUTMENT ;
    PORT
      LAYER M3 ;
      RECT 23.751 0.000 23.769 0.054 ;
    END
  END r0_rd_out[17]
  PIN r0_rd_out[18]
    DIRECTION OUTPUT ;
    USE SIGNAL ;
    SHAPE ABUTMENT ;
    PORT
      LAYER M3 ;
      RECT 23.967 0.000 23.985 0.054 ;
    END
  END r0_rd_out[18]
  PIN r0_rd_out[19]
    DIRECTION OUTPUT ;
    USE SIGNAL ;
    SHAPE ABUTMENT ;
    PORT
      LAYER M3 ;
      RECT 24.183 0.000 24.201 0.054 ;
    END
  END r0_rd_out[19]
  PIN r0_rd_out[20]
    DIRECTION OUTPUT ;
    USE SIGNAL ;
    SHAPE ABUTMENT ;
    PORT
      LAYER M3 ;
      RECT 24.399 0.000 24.417 0.054 ;
    END
  END r0_rd_out[20]
  PIN r0_rd_out[21]
    DIRECTION OUTPUT ;
    USE SIGNAL ;
    SHAPE ABUTMENT ;
    PORT
      LAYER M3 ;
      RECT 24.615 0.000 24.633 0.054 ;
    END
  END r0_rd_out[21]
  PIN r0_rd_out[22]
    DIRECTION OUTPUT ;
    USE SIGNAL ;
    SHAPE ABUTMENT ;
    PORT
      LAYER M3 ;
      RECT 24.831 0.000 24.849 0.054 ;
    END
  END r0_rd_out[22]
  PIN r0_rd_out[23]
    DIRECTION OUTPUT ;
    USE SIGNAL ;
    SHAPE ABUTMENT ;
    PORT
      LAYER M3 ;
      RECT 25.047 0.000 25.065 0.054 ;
    END
  END r0_rd_out[23]
  PIN r0_rd_out[24]
    DIRECTION OUTPUT ;
    USE SIGNAL ;
    SHAPE ABUTMENT ;
    PORT
      LAYER M3 ;
      RECT 25.263 0.000 25.281 0.054 ;
    END
  END r0_rd_out[24]
  PIN r0_rd_out[25]
    DIRECTION OUTPUT ;
    USE SIGNAL ;
    SHAPE ABUTMENT ;
    PORT
      LAYER M3 ;
      RECT 25.479 0.000 25.497 0.054 ;
    END
  END r0_rd_out[25]
  PIN r0_rd_out[26]
    DIRECTION OUTPUT ;
    USE SIGNAL ;
    SHAPE ABUTMENT ;
    PORT
      LAYER M3 ;
      RECT 25.695 0.000 25.713 0.054 ;
    END
  END r0_rd_out[26]
  PIN r0_rd_out[27]
    DIRECTION OUTPUT ;
    USE SIGNAL ;
    SHAPE ABUTMENT ;
    PORT
      LAYER M3 ;
      RECT 25.911 0.000 25.929 0.054 ;
    END
  END r0_rd_out[27]
  PIN r0_rd_out[28]
    DIRECTION OUTPUT ;
    USE SIGNAL ;
    SHAPE ABUTMENT ;
    PORT
      LAYER M3 ;
      RECT 26.127 0.000 26.145 0.054 ;
    END
  END r0_rd_out[28]
  PIN r0_rd_out[29]
    DIRECTION OUTPUT ;
    USE SIGNAL ;
    SHAPE ABUTMENT ;
    PORT
      LAYER M3 ;
      RECT 26.343 0.000 26.361 0.054 ;
    END
  END r0_rd_out[29]
  PIN r0_rd_out[30]
    DIRECTION OUTPUT ;
    USE SIGNAL ;
    SHAPE ABUTMENT ;
    PORT
      LAYER M3 ;
      RECT 26.559 0.000 26.577 0.054 ;
    END
  END r0_rd_out[30]
  PIN r0_rd_out[31]
    DIRECTION OUTPUT ;
    USE SIGNAL ;
    SHAPE ABUTMENT ;
    PORT
      LAYER M3 ;
      RECT 26.775 0.000 26.793 0.054 ;
    END
  END r0_rd_out[31]
  PIN r0_rd_out[32]
    DIRECTION OUTPUT ;
    USE SIGNAL ;
    SHAPE ABUTMENT ;
    PORT
      LAYER M3 ;
      RECT 26.991 0.000 27.009 0.054 ;
    END
  END r0_rd_out[32]
  PIN r0_rd_out[33]
    DIRECTION OUTPUT ;
    USE SIGNAL ;
    SHAPE ABUTMENT ;
    PORT
      LAYER M3 ;
      RECT 27.207 0.000 27.225 0.054 ;
    END
  END r0_rd_out[33]
  PIN r0_rd_out[34]
    DIRECTION OUTPUT ;
    USE SIGNAL ;
    SHAPE ABUTMENT ;
    PORT
      LAYER M3 ;
      RECT 27.423 0.000 27.441 0.054 ;
    END
  END r0_rd_out[34]
  PIN r0_rd_out[35]
    DIRECTION OUTPUT ;
    USE SIGNAL ;
    SHAPE ABUTMENT ;
    PORT
      LAYER M3 ;
      RECT 27.639 0.000 27.657 0.054 ;
    END
  END r0_rd_out[35]
  PIN r0_rd_out[36]
    DIRECTION OUTPUT ;
    USE SIGNAL ;
    SHAPE ABUTMENT ;
    PORT
      LAYER M3 ;
      RECT 27.855 0.000 27.873 0.054 ;
    END
  END r0_rd_out[36]
  PIN r0_rd_out[37]
    DIRECTION OUTPUT ;
    USE SIGNAL ;
    SHAPE ABUTMENT ;
    PORT
      LAYER M3 ;
      RECT 28.071 0.000 28.089 0.054 ;
    END
  END r0_rd_out[37]
  PIN r0_rd_out[38]
    DIRECTION OUTPUT ;
    USE SIGNAL ;
    SHAPE ABUTMENT ;
    PORT
      LAYER M3 ;
      RECT 28.287 0.000 28.305 0.054 ;
    END
  END r0_rd_out[38]
  PIN r0_rd_out[39]
    DIRECTION OUTPUT ;
    USE SIGNAL ;
    SHAPE ABUTMENT ;
    PORT
      LAYER M3 ;
      RECT 28.503 0.000 28.521 0.054 ;
    END
  END r0_rd_out[39]
  PIN r0_rd_out[40]
    DIRECTION OUTPUT ;
    USE SIGNAL ;
    SHAPE ABUTMENT ;
    PORT
      LAYER M3 ;
      RECT 28.719 0.000 28.737 0.054 ;
    END
  END r0_rd_out[40]
  PIN r0_rd_out[41]
    DIRECTION OUTPUT ;
    USE SIGNAL ;
    SHAPE ABUTMENT ;
    PORT
      LAYER M3 ;
      RECT 28.935 0.000 28.953 0.054 ;
    END
  END r0_rd_out[41]
  PIN r0_rd_out[42]
    DIRECTION OUTPUT ;
    USE SIGNAL ;
    SHAPE ABUTMENT ;
    PORT
      LAYER M3 ;
      RECT 29.151 0.000 29.169 0.054 ;
    END
  END r0_rd_out[42]
  PIN r0_rd_out[43]
    DIRECTION OUTPUT ;
    USE SIGNAL ;
    SHAPE ABUTMENT ;
    PORT
      LAYER M3 ;
      RECT 29.367 0.000 29.385 0.054 ;
    END
  END r0_rd_out[43]
  PIN r0_rd_out[44]
    DIRECTION OUTPUT ;
    USE SIGNAL ;
    SHAPE ABUTMENT ;
    PORT
      LAYER M3 ;
      RECT 29.583 0.000 29.601 0.054 ;
    END
  END r0_rd_out[44]
  PIN r0_rd_out[45]
    DIRECTION OUTPUT ;
    USE SIGNAL ;
    SHAPE ABUTMENT ;
    PORT
      LAYER M3 ;
      RECT 29.799 0.000 29.817 0.054 ;
    END
  END r0_rd_out[45]
  PIN r0_rd_out[46]
    DIRECTION OUTPUT ;
    USE SIGNAL ;
    SHAPE ABUTMENT ;
    PORT
      LAYER M3 ;
      RECT 13.455 55.394 13.473 55.448 ;
    END
  END r0_rd_out[46]
  PIN r0_rd_out[47]
    DIRECTION OUTPUT ;
    USE SIGNAL ;
    SHAPE ABUTMENT ;
    PORT
      LAYER M3 ;
      RECT 13.743 55.394 13.761 55.448 ;
    END
  END r0_rd_out[47]
  PIN r0_rd_out[48]
    DIRECTION OUTPUT ;
    USE SIGNAL ;
    SHAPE ABUTMENT ;
    PORT
      LAYER M3 ;
      RECT 14.031 55.394 14.049 55.448 ;
    END
  END r0_rd_out[48]
  PIN r0_rd_out[49]
    DIRECTION OUTPUT ;
    USE SIGNAL ;
    SHAPE ABUTMENT ;
    PORT
      LAYER M3 ;
      RECT 14.319 55.394 14.337 55.448 ;
    END
  END r0_rd_out[49]
  PIN r0_rd_out[50]
    DIRECTION OUTPUT ;
    USE SIGNAL ;
    SHAPE ABUTMENT ;
    PORT
      LAYER M3 ;
      RECT 14.607 55.394 14.625 55.448 ;
    END
  END r0_rd_out[50]
  PIN r0_rd_out[51]
    DIRECTION OUTPUT ;
    USE SIGNAL ;
    SHAPE ABUTMENT ;
    PORT
      LAYER M3 ;
      RECT 14.895 55.394 14.913 55.448 ;
    END
  END r0_rd_out[51]
  PIN r0_rd_out[52]
    DIRECTION OUTPUT ;
    USE SIGNAL ;
    SHAPE ABUTMENT ;
    PORT
      LAYER M3 ;
      RECT 15.183 55.394 15.201 55.448 ;
    END
  END r0_rd_out[52]
  PIN r0_rd_out[53]
    DIRECTION OUTPUT ;
    USE SIGNAL ;
    SHAPE ABUTMENT ;
    PORT
      LAYER M3 ;
      RECT 15.471 55.394 15.489 55.448 ;
    END
  END r0_rd_out[53]
  PIN r0_rd_out[54]
    DIRECTION OUTPUT ;
    USE SIGNAL ;
    SHAPE ABUTMENT ;
    PORT
      LAYER M3 ;
      RECT 15.759 55.394 15.777 55.448 ;
    END
  END r0_rd_out[54]
  PIN r0_rd_out[55]
    DIRECTION OUTPUT ;
    USE SIGNAL ;
    SHAPE ABUTMENT ;
    PORT
      LAYER M3 ;
      RECT 16.047 55.394 16.065 55.448 ;
    END
  END r0_rd_out[55]
  PIN r0_rd_out[56]
    DIRECTION OUTPUT ;
    USE SIGNAL ;
    SHAPE ABUTMENT ;
    PORT
      LAYER M3 ;
      RECT 16.335 55.394 16.353 55.448 ;
    END
  END r0_rd_out[56]
  PIN r0_rd_out[57]
    DIRECTION OUTPUT ;
    USE SIGNAL ;
    SHAPE ABUTMENT ;
    PORT
      LAYER M3 ;
      RECT 16.623 55.394 16.641 55.448 ;
    END
  END r0_rd_out[57]
  PIN r0_rd_out[58]
    DIRECTION OUTPUT ;
    USE SIGNAL ;
    SHAPE ABUTMENT ;
    PORT
      LAYER M3 ;
      RECT 16.911 55.394 16.929 55.448 ;
    END
  END r0_rd_out[58]
  PIN r0_rd_out[59]
    DIRECTION OUTPUT ;
    USE SIGNAL ;
    SHAPE ABUTMENT ;
    PORT
      LAYER M3 ;
      RECT 17.199 55.394 17.217 55.448 ;
    END
  END r0_rd_out[59]
  PIN r0_rd_out[60]
    DIRECTION OUTPUT ;
    USE SIGNAL ;
    SHAPE ABUTMENT ;
    PORT
      LAYER M3 ;
      RECT 17.487 55.394 17.505 55.448 ;
    END
  END r0_rd_out[60]
  PIN r0_rd_out[61]
    DIRECTION OUTPUT ;
    USE SIGNAL ;
    SHAPE ABUTMENT ;
    PORT
      LAYER M3 ;
      RECT 17.775 55.394 17.793 55.448 ;
    END
  END r0_rd_out[61]
  PIN r0_rd_out[62]
    DIRECTION OUTPUT ;
    USE SIGNAL ;
    SHAPE ABUTMENT ;
    PORT
      LAYER M3 ;
      RECT 18.063 55.394 18.081 55.448 ;
    END
  END r0_rd_out[62]
  PIN r0_rd_out[63]
    DIRECTION OUTPUT ;
    USE SIGNAL ;
    SHAPE ABUTMENT ;
    PORT
      LAYER M3 ;
      RECT 18.351 55.394 18.369 55.448 ;
    END
  END r0_rd_out[63]
  PIN r0_rd_out[64]
    DIRECTION OUTPUT ;
    USE SIGNAL ;
    SHAPE ABUTMENT ;
    PORT
      LAYER M3 ;
      RECT 18.639 55.394 18.657 55.448 ;
    END
  END r0_rd_out[64]
  PIN r0_rd_out[65]
    DIRECTION OUTPUT ;
    USE SIGNAL ;
    SHAPE ABUTMENT ;
    PORT
      LAYER M3 ;
      RECT 18.927 55.394 18.945 55.448 ;
    END
  END r0_rd_out[65]
  PIN r0_rd_out[66]
    DIRECTION OUTPUT ;
    USE SIGNAL ;
    SHAPE ABUTMENT ;
    PORT
      LAYER M3 ;
      RECT 19.215 55.394 19.233 55.448 ;
    END
  END r0_rd_out[66]
  PIN r0_rd_out[67]
    DIRECTION OUTPUT ;
    USE SIGNAL ;
    SHAPE ABUTMENT ;
    PORT
      LAYER M3 ;
      RECT 19.503 55.394 19.521 55.448 ;
    END
  END r0_rd_out[67]
  PIN r0_rd_out[68]
    DIRECTION OUTPUT ;
    USE SIGNAL ;
    SHAPE ABUTMENT ;
    PORT
      LAYER M3 ;
      RECT 19.791 55.394 19.809 55.448 ;
    END
  END r0_rd_out[68]
  PIN r0_rd_out[69]
    DIRECTION OUTPUT ;
    USE SIGNAL ;
    SHAPE ABUTMENT ;
    PORT
      LAYER M3 ;
      RECT 20.079 55.394 20.097 55.448 ;
    END
  END r0_rd_out[69]
  PIN r0_rd_out[70]
    DIRECTION OUTPUT ;
    USE SIGNAL ;
    SHAPE ABUTMENT ;
    PORT
      LAYER M3 ;
      RECT 20.367 55.394 20.385 55.448 ;
    END
  END r0_rd_out[70]
  PIN r0_rd_out[71]
    DIRECTION OUTPUT ;
    USE SIGNAL ;
    SHAPE ABUTMENT ;
    PORT
      LAYER M3 ;
      RECT 20.655 55.394 20.673 55.448 ;
    END
  END r0_rd_out[71]
  PIN r0_rd_out[72]
    DIRECTION OUTPUT ;
    USE SIGNAL ;
    SHAPE ABUTMENT ;
    PORT
      LAYER M3 ;
      RECT 20.943 55.394 20.961 55.448 ;
    END
  END r0_rd_out[72]
  PIN r0_rd_out[73]
    DIRECTION OUTPUT ;
    USE SIGNAL ;
    SHAPE ABUTMENT ;
    PORT
      LAYER M3 ;
      RECT 21.231 55.394 21.249 55.448 ;
    END
  END r0_rd_out[73]
  PIN r0_rd_out[74]
    DIRECTION OUTPUT ;
    USE SIGNAL ;
    SHAPE ABUTMENT ;
    PORT
      LAYER M3 ;
      RECT 21.519 55.394 21.537 55.448 ;
    END
  END r0_rd_out[74]
  PIN r0_rd_out[75]
    DIRECTION OUTPUT ;
    USE SIGNAL ;
    SHAPE ABUTMENT ;
    PORT
      LAYER M3 ;
      RECT 21.807 55.394 21.825 55.448 ;
    END
  END r0_rd_out[75]
  PIN r0_rd_out[76]
    DIRECTION OUTPUT ;
    USE SIGNAL ;
    SHAPE ABUTMENT ;
    PORT
      LAYER M3 ;
      RECT 22.095 55.394 22.113 55.448 ;
    END
  END r0_rd_out[76]
  PIN r0_rd_out[77]
    DIRECTION OUTPUT ;
    USE SIGNAL ;
    SHAPE ABUTMENT ;
    PORT
      LAYER M3 ;
      RECT 22.383 55.394 22.401 55.448 ;
    END
  END r0_rd_out[77]
  PIN r0_rd_out[78]
    DIRECTION OUTPUT ;
    USE SIGNAL ;
    SHAPE ABUTMENT ;
    PORT
      LAYER M3 ;
      RECT 22.671 55.394 22.689 55.448 ;
    END
  END r0_rd_out[78]
  PIN r0_rd_out[79]
    DIRECTION OUTPUT ;
    USE SIGNAL ;
    SHAPE ABUTMENT ;
    PORT
      LAYER M3 ;
      RECT 22.959 55.394 22.977 55.448 ;
    END
  END r0_rd_out[79]
  PIN r0_rd_out[80]
    DIRECTION OUTPUT ;
    USE SIGNAL ;
    SHAPE ABUTMENT ;
    PORT
      LAYER M3 ;
      RECT 23.247 55.394 23.265 55.448 ;
    END
  END r0_rd_out[80]
  PIN r0_rd_out[81]
    DIRECTION OUTPUT ;
    USE SIGNAL ;
    SHAPE ABUTMENT ;
    PORT
      LAYER M3 ;
      RECT 23.535 55.394 23.553 55.448 ;
    END
  END r0_rd_out[81]
  PIN r0_rd_out[82]
    DIRECTION OUTPUT ;
    USE SIGNAL ;
    SHAPE ABUTMENT ;
    PORT
      LAYER M3 ;
      RECT 23.823 55.394 23.841 55.448 ;
    END
  END r0_rd_out[82]
  PIN r0_rd_out[83]
    DIRECTION OUTPUT ;
    USE SIGNAL ;
    SHAPE ABUTMENT ;
    PORT
      LAYER M3 ;
      RECT 24.111 55.394 24.129 55.448 ;
    END
  END r0_rd_out[83]
  PIN r0_rd_out[84]
    DIRECTION OUTPUT ;
    USE SIGNAL ;
    SHAPE ABUTMENT ;
    PORT
      LAYER M3 ;
      RECT 24.399 55.394 24.417 55.448 ;
    END
  END r0_rd_out[84]
  PIN r0_rd_out[85]
    DIRECTION OUTPUT ;
    USE SIGNAL ;
    SHAPE ABUTMENT ;
    PORT
      LAYER M3 ;
      RECT 24.687 55.394 24.705 55.448 ;
    END
  END r0_rd_out[85]
  PIN r0_rd_out[86]
    DIRECTION OUTPUT ;
    USE SIGNAL ;
    SHAPE ABUTMENT ;
    PORT
      LAYER M3 ;
      RECT 24.975 55.394 24.993 55.448 ;
    END
  END r0_rd_out[86]
  PIN r0_rd_out[87]
    DIRECTION OUTPUT ;
    USE SIGNAL ;
    SHAPE ABUTMENT ;
    PORT
      LAYER M3 ;
      RECT 25.263 55.394 25.281 55.448 ;
    END
  END r0_rd_out[87]
  PIN r0_rd_out[88]
    DIRECTION OUTPUT ;
    USE SIGNAL ;
    SHAPE ABUTMENT ;
    PORT
      LAYER M3 ;
      RECT 25.551 55.394 25.569 55.448 ;
    END
  END r0_rd_out[88]
  PIN r0_rd_out[89]
    DIRECTION OUTPUT ;
    USE SIGNAL ;
    SHAPE ABUTMENT ;
    PORT
      LAYER M3 ;
      RECT 25.839 55.394 25.857 55.448 ;
    END
  END r0_rd_out[89]
  PIN r0_rd_out[90]
    DIRECTION OUTPUT ;
    USE SIGNAL ;
    SHAPE ABUTMENT ;
    PORT
      LAYER M3 ;
      RECT 26.127 55.394 26.145 55.448 ;
    END
  END r0_rd_out[90]
  PIN r0_rd_out[91]
    DIRECTION OUTPUT ;
    USE SIGNAL ;
    SHAPE ABUTMENT ;
    PORT
      LAYER M3 ;
      RECT 26.415 55.394 26.433 55.448 ;
    END
  END r0_rd_out[91]
  PIN rw0_addr_in[0]
    DIRECTION INPUT ;
    USE SIGNAL ;
    SHAPE ABUTMENT ;
    PORT
      LAYER M4 ;
      RECT 0.000 40.020 0.072 40.044 ;
    END
  END rw0_addr_in[0]
  PIN rw0_addr_in[1]
    DIRECTION INPUT ;
    USE SIGNAL ;
    SHAPE ABUTMENT ;
    PORT
      LAYER M4 ;
      RECT 0.000 41.748 0.072 41.772 ;
    END
  END rw0_addr_in[1]
  PIN rw0_addr_in[2]
    DIRECTION INPUT ;
    USE SIGNAL ;
    SHAPE ABUTMENT ;
    PORT
      LAYER M4 ;
      RECT 0.000 43.476 0.072 43.500 ;
    END
  END rw0_addr_in[2]
  PIN rw0_addr_in[3]
    DIRECTION INPUT ;
    USE SIGNAL ;
    SHAPE ABUTMENT ;
    PORT
      LAYER M4 ;
      RECT 0.000 45.204 0.072 45.228 ;
    END
  END rw0_addr_in[3]
  PIN rw0_addr_in[4]
    DIRECTION INPUT ;
    USE SIGNAL ;
    SHAPE ABUTMENT ;
    PORT
      LAYER M4 ;
      RECT 30.333 40.020 30.405 40.044 ;
    END
  END rw0_addr_in[4]
  PIN rw0_addr_in[5]
    DIRECTION INPUT ;
    USE SIGNAL ;
    SHAPE ABUTMENT ;
    PORT
      LAYER M4 ;
      RECT 30.333 41.748 30.405 41.772 ;
    END
  END rw0_addr_in[5]
  PIN rw0_addr_in[6]
    DIRECTION INPUT ;
    USE SIGNAL ;
    SHAPE ABUTMENT ;
    PORT
      LAYER M4 ;
      RECT 30.333 43.476 30.405 43.500 ;
    END
  END rw0_addr_in[6]
  PIN rw0_addr_in[7]
    DIRECTION INPUT ;
    USE SIGNAL ;
    SHAPE ABUTMENT ;
    PORT
      LAYER M4 ;
      RECT 30.333 45.204 30.405 45.228 ;
    END
  END rw0_addr_in[7]
  PIN r0_addr_in[0]
    DIRECTION INPUT ;
    USE SIGNAL ;
    SHAPE ABUTMENT ;
    PORT
      LAYER M4 ;
      RECT 0.000 46.932 0.072 46.956 ;
    END
  END r0_addr_in[0]
  PIN r0_addr_in[1]
    DIRECTION INPUT ;
    USE SIGNAL ;
    SHAPE ABUTMENT ;
    PORT
      LAYER M4 ;
      RECT 0.000 48.660 0.072 48.684 ;
    END
  END r0_addr_in[1]
  PIN r0_addr_in[2]
    DIRECTION INPUT ;
    USE SIGNAL ;
    SHAPE ABUTMENT ;
    PORT
      LAYER M4 ;
      RECT 0.000 50.388 0.072 50.412 ;
    END
  END r0_addr_in[2]
  PIN r0_addr_in[3]
    DIRECTION INPUT ;
    USE SIGNAL ;
    SHAPE ABUTMENT ;
    PORT
      LAYER M4 ;
      RECT 0.000 52.116 0.072 52.140 ;
    END
  END r0_addr_in[3]
  PIN r0_addr_in[4]
    DIRECTION INPUT ;
    USE SIGNAL ;
    SHAPE ABUTMENT ;
    PORT
      LAYER M4 ;
      RECT 30.333 46.932 30.405 46.956 ;
    END
  END r0_addr_in[4]
  PIN r0_addr_in[5]
    DIRECTION INPUT ;
    USE SIGNAL ;
    SHAPE ABUTMENT ;
    PORT
      LAYER M4 ;
      RECT 30.333 48.660 30.405 48.684 ;
    END
  END r0_addr_in[5]
  PIN r0_addr_in[6]
    DIRECTION INPUT ;
    USE SIGNAL ;
    SHAPE ABUTMENT ;
    PORT
      LAYER M4 ;
      RECT 30.333 50.388 30.405 50.412 ;
    END
  END r0_addr_in[6]
  PIN r0_addr_in[7]
    DIRECTION INPUT ;
    USE SIGNAL ;
    SHAPE ABUTMENT ;
    PORT
      LAYER M4 ;
      RECT 30.333 52.116 30.405 52.140 ;
    END
  END r0_addr_in[7]
  PIN rw0_we_in
    DIRECTION INPUT ;
    USE SIGNAL ;
    SHAPE ABUTMENT ;
    PORT
      LAYER M3 ;
      RECT 26.703 55.394 26.721 55.448 ;
    END
  END rw0_we_in
  PIN rw0_ce_in
    DIRECTION INPUT ;
    USE SIGNAL ;
    SHAPE ABUTMENT ;
    PORT
      LAYER M3 ;
      RECT 26.991 55.394 27.009 55.448 ;
    END
  END rw0_ce_in
  PIN rw0_clk
    DIRECTION INPUT ;
    USE SIGNAL ;
    SHAPE ABUTMENT ;
    PORT
      LAYER M3 ;
      RECT 27.279 55.394 27.297 55.448 ;
    END
  END rw0_clk
  PIN r0_ce_in
    DIRECTION INPUT ;
    USE SIGNAL ;
    SHAPE ABUTMENT ;
    PORT
      LAYER M3 ;
      RECT 27.567 55.394 27.585 55.448 ;
    END
  END r0_ce_in
  PIN r0_clk
    DIRECTION INPUT ;
    USE SIGNAL ;
    SHAPE ABUTMENT ;
    PORT
      LAYER M3 ;
      RECT 27.855 55.394 27.873 55.448 ;
    END
  END r0_clk
  PIN VSS
    DIRECTION INOUT ;
    USE GROUND ;
    PORT
      LAYER M4 ;
      RECT 0.216 0.240 30.189 0.336 ;
      RECT 0.216 1.008 30.189 1.104 ;
      RECT 0.216 1.776 30.189 1.872 ;
      RECT 0.216 2.544 30.189 2.640 ;
      RECT 0.216 3.312 30.189 3.408 ;
      RECT 0.216 4.080 30.189 4.176 ;
      RECT 0.216 4.848 30.189 4.944 ;
      RECT 0.216 5.616 30.189 5.712 ;
      RECT 0.216 6.384 30.189 6.480 ;
      RECT 0.216 7.152 30.189 7.248 ;
      RECT 0.216 7.920 30.189 8.016 ;
      RECT 0.216 8.688 30.189 8.784 ;
      RECT 0.216 9.456 30.189 9.552 ;
      RECT 0.216 10.224 30.189 10.320 ;
      RECT 0.216 10.992 30.189 11.088 ;
      RECT 0.216 11.760 30.189 11.856 ;
      RECT 0.216 12.528 30.189 12.624 ;
      RECT 0.216 13.296 30.189 13.392 ;
      RECT 0.216 14.064 30.189 14.160 ;
      RECT 0.216 14.832 30.189 14.928 ;
      RECT 0.216 15.600 30.189 15.696 ;
      RECT 0.216 16.368 30.189 16.464 ;
      RECT 0.216 17.136 30.189 17.232 ;
      RECT 0.216 17.904 30.189 18.000 ;
      RECT 0.216 18.672 30.189 18.768 ;
      RECT 0.216 19.440 30.189 19.536 ;
      RECT 0.216 20.208 30.189 20.304 ;
      RECT 0.216 20.976 30.189 21.072 ;
      RECT 0.216 21.744 30.189 21.840 ;
      RECT 0.216 22.512 30.189 22.608 ;
      RECT 0.216 23.280 30.189 23.376 ;
      RECT 0.216 24.048 30.189 24.144 ;
      RECT 0.216 24.816 30.189 24.912 ;
      RECT 0.216 25.584 30.189 25.680 ;
      RECT 0.216 26.352 30.189 26.448 ;
      RECT 0.216 27.120 30.189 27.216 ;
      RECT 0.216 27.888 30.189 27.984 ;
      RECT 0.216 28.656 30.189 28.752 ;
      RECT 0.216 29.424 30.189 29.520 ;
      RECT 0.216 30.192 30.189 30.288 ;
      RECT 0.216 30.960 30.189 31.056 ;
      RECT 0.216 31.728 30.189 31.824 ;
      RECT 0.216 32.496 30.189 32.592 ;
      RECT 0.216 33.264 30.189 33.360 ;
      RECT 0.216 34.032 30.189 34.128 ;
      RECT 0.216 34.800 30.189 34.896 ;
      RECT 0.216 35.568 30.189 35.664 ;
      RECT 0.216 36.336 30.189 36.432 ;
      RECT 0.216 37.104 30.189 37.200 ;
      RECT 0.216 37.872 30.189 37.968 ;
      RECT 0.216 38.640 30.189 38.736 ;
      RECT 0.216 39.408 30.189 39.504 ;
      RECT 0.216 40.176 30.189 40.272 ;
      RECT 0.216 40.944 30.189 41.040 ;
      RECT 0.216 41.712 30.189 41.808 ;
      RECT 0.216 42.480 30.189 42.576 ;
      RECT 0.216 43.248 30.189 43.344 ;
      RECT 0.216 44.016 30.189 44.112 ;
      RECT 0.216 44.784 30.189 44.880 ;
      RECT 0.216 45.552 30.189 45.648 ;
      RECT 0.216 46.320 30.189 46.416 ;
      RECT 0.216 47.088 30.189 47.184 ;
      RECT 0.216 47.856 30.189 47.952 ;
      RECT 0.216 48.624 30.189 48.720 ;
      RECT 0.216 49.392 30.189 49.488 ;
      RECT 0.216 50.160 30.189 50.256 ;
      RECT 0.216 50.928 30.189 51.024 ;
      RECT 0.216 51.696 30.189 51.792 ;
      RECT 0.216 52.464 30.189 52.560 ;
      RECT 0.216 53.232 30.189 53.328 ;
      RECT 0.216 54.000 30.189 54.096 ;
      RECT 0.216 54.768 30.189 54.864 ;
    END
  END VSS
  PIN VDD
    DIRECTION INOUT ;
    USE POWER ;
    PORT
      LAYER M4 ;
      RECT 0.216 0.240 30.189 0.336 ;
      RECT 0.216 1.008 30.189 1.104 ;
      RECT 0.216 1.776 30.189 1.872 ;
      RECT 0.216 2.544 30.189 2.640 ;
      RECT 0.216 3.312 30.189 3.408 ;
      RECT 0.216 4.080 30.189 4.176 ;
      RECT 0.216 4.848 30.189 4.944 ;
      RECT 0.216 5.616 30.189 5.712 ;
      RECT 0.216 6.384 30.189 6.480 ;
      RECT 0.216 7.152 30.189 7.248 ;
      RECT 0.216 7.920 30.189 8.016 ;
      RECT 0.216 8.688 30.189 8.784 ;
      RECT 0.216 9.456 30.189 9.552 ;
      RECT 0.216 10.224 30.189 10.320 ;
      RECT 0.216 10.992 30.189 11.088 ;
      RECT 0.216 11.760 30.189 11.856 ;
      RECT 0.216 12.528 30.189 12.624 ;
      RECT 0.216 13.296 30.189 13.392 ;
      RECT 0.216 14.064 30.189 14.160 ;
      RECT 0.216 14.832 30.189 14.928 ;
      RECT 0.216 15.600 30.189 15.696 ;
      RECT 0.216 16.368 30.189 16.464 ;
      RECT 0.216 17.136 30.189 17.232 ;
      RECT 0.216 17.904 30.189 18.000 ;
      RECT 0.216 18.672 30.189 18.768 ;
      RECT 0.216 19.440 30.189 19.536 ;
      RECT 0.216 20.208 30.189 20.304 ;
      RECT 0.216 20.976 30.189 21.072 ;
      RECT 0.216 21.744 30.189 21.840 ;
      RECT 0.216 22.512 30.189 22.608 ;
      RECT 0.216 23.280 30.189 23.376 ;
      RECT 0.216 24.048 30.189 24.144 ;
      RECT 0.216 24.816 30.189 24.912 ;
      RECT 0.216 25.584 30.189 25.680 ;
      RECT 0.216 26.352 30.189 26.448 ;
      RECT 0.216 27.120 30.189 27.216 ;
      RECT 0.216 27.888 30.189 27.984 ;
      RECT 0.216 28.656 30.189 28.752 ;
      RECT 0.216 29.424 30.189 29.520 ;
      RECT 0.216 30.192 30.189 30.288 ;
      RECT 0.216 30.960 30.189 31.056 ;
      RECT 0.216 31.728 30.189 31.824 ;
      RECT 0.216 32.496 30.189 32.592 ;
      RECT 0.216 33.264 30.189 33.360 ;
      RECT 0.216 34.032 30.189 34.128 ;
      RECT 0.216 34.800 30.189 34.896 ;
      RECT 0.216 35.568 30.189 35.664 ;
      RECT 0.216 36.336 30.189 36.432 ;
      RECT 0.216 37.104 30.189 37.200 ;
      RECT 0.216 37.872 30.189 37.968 ;
      RECT 0.216 38.640 30.189 38.736 ;
      RECT 0.216 39.408 30.189 39.504 ;
      RECT 0.216 40.176 30.189 40.272 ;
      RECT 0.216 40.944 30.189 41.040 ;
      RECT 0.216 41.712 30.189 41.808 ;
      RECT 0.216 42.480 30.189 42.576 ;
      RECT 0.216 43.248 30.189 43.344 ;
      RECT 0.216 44.016 30.189 44.112 ;
      RECT 0.216 44.784 30.189 44.880 ;
      RECT 0.216 45.552 30.189 45.648 ;
      RECT 0.216 46.320 30.189 46.416 ;
      RECT 0.216 47.088 30.189 47.184 ;
      RECT 0.216 47.856 30.189 47.952 ;
      RECT 0.216 48.624 30.189 48.720 ;
      RECT 0.216 49.392 30.189 49.488 ;
      RECT 0.216 50.160 30.189 50.256 ;
      RECT 0.216 50.928 30.189 51.024 ;
      RECT 0.216 51.696 30.189 51.792 ;
      RECT 0.216 52.464 30.189 52.560 ;
      RECT 0.216 53.232 30.189 53.328 ;
      RECT 0.216 54.000 30.189 54.096 ;
      RECT 0.216 54.768 30.189 54.864 ;
    END
  END VDD
  OBS
    LAYER M1 ;
    RECT 0 0 30.405 55.448 ;
    LAYER M2 ;
    RECT 0 0 30.405 55.448 ;
    LAYER M3 ;
    RECT 0 0 30.405 55.448 ;
    LAYER M4 ;
    RECT 0 0 30.405 55.448 ;
  END
END fakeram_1rw1r_92w256d_sram

END LIBRARY
